One B-rep face of a CAD part: STEP entity #1128.
In plain terms, the planar face has unit normal (1, 0, 0).
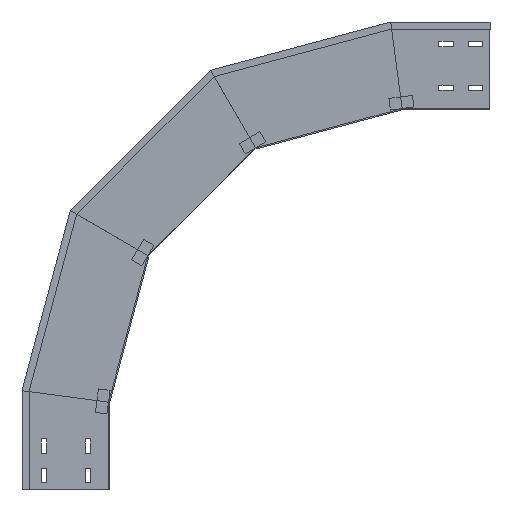
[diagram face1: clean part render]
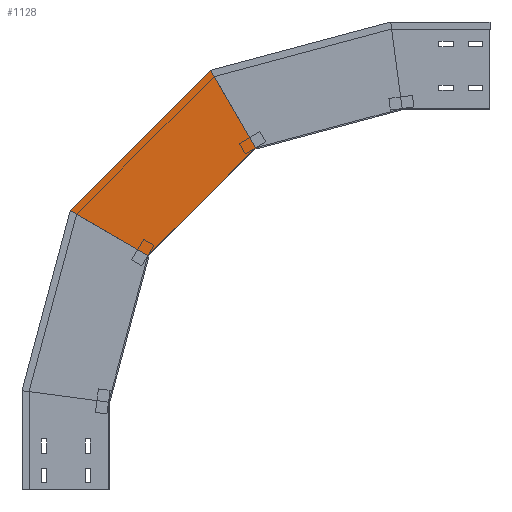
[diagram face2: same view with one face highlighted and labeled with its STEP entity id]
Its self-contained STEP definition (entity closure, numbers rounded to 3 decimals):
#20 = DIRECTION ( 'NONE',  ( 0., -0.5, -0.866 ) ) ;
#107 = CARTESIAN_POINT ( 'NONE',  ( 0., -250.175, 583.315 ) ) ;
#182 = EDGE_CURVE ( 'NONE', #1970, #1149, #2250, .T. ) ;
#220 = CARTESIAN_POINT ( 'NONE',  ( 0., -129.979, 363.834 ) ) ;
#388 = VECTOR ( 'NONE', #1787, 1000. ) ;
#463 = CARTESIAN_POINT ( 'NONE',  ( 0., -67.034, 400.175 ) ) ;
#530 = EDGE_CURVE ( 'NONE', #822, #1149, #2233, .T. ) ;
#629 = VERTEX_POINT ( 'NONE', #1124 ) ;
#787 = ORIENTED_EDGE ( 'NONE', *, *, #1533, .T. ) ;
#822 = VERTEX_POINT ( 'NONE', #1441 ) ;
#869 = EDGE_CURVE ( 'NONE', #629, #1970, #2286, .T. ) ;
#895 = DIRECTION ( 'NONE',  ( 1., 0., 0. ) ) ;
#1022 = CARTESIAN_POINT ( 'NONE',  ( 0., -35.701, 368.842 ) ) ;
#1105 = DIRECTION ( 'NONE',  ( 0., -0.707, 0.707 ) ) ;
#1124 = CARTESIAN_POINT ( 'NONE',  ( 0., 67.452, 477.821 ) ) ;
#1128 = ADVANCED_FACE ( 'NONE', ( #2009 ), #1277, .T. ) ;
#1149 = VERTEX_POINT ( 'NONE', #107 ) ;
#1277 = PLANE ( 'NONE',  #1401 ) ;
#1343 = DIRECTION ( 'NONE',  ( 0., -0.866, -0.5 ) ) ;
#1401 = AXIS2_PLACEMENT_3D ( 'NONE', #1022, #895, #2380 ) ;
#1406 = CARTESIAN_POINT ( 'NONE',  ( 0., 70.365, 474.908 ) ) ;
#1414 = VECTOR ( 'NONE', #20, 1000. ) ;
#1429 = ORIENTED_EDGE ( 'NONE', *, *, #182, .F. ) ;
#1441 = CARTESIAN_POINT ( 'NONE',  ( 0., -172.529, 717.802 ) ) ;
#1471 = ORIENTED_EDGE ( 'NONE', *, *, #869, .F. ) ;
#1533 = EDGE_CURVE ( 'NONE', #629, #822, #1620, .T. ) ;
#1620 = LINE ( 'NONE', #1406, #388 ) ;
#1787 = DIRECTION ( 'NONE',  ( 0., -0.707, 0.707 ) ) ;
#1858 = CARTESIAN_POINT ( 'NONE',  ( 0., -35.701, 368.842 ) ) ;
#1928 = EDGE_LOOP ( 'NONE', ( #787, #2375, #1429, #1471 ) ) ;
#1935 = VECTOR ( 'NONE', #1343, 1000. ) ;
#1970 = VERTEX_POINT ( 'NONE', #463 ) ;
#2009 = FACE_OUTER_BOUND ( 'NONE', #1928, .T. ) ;
#2233 = LINE ( 'NONE', #2267, #1414 ) ;
#2250 = LINE ( 'NONE', #1858, #2274 ) ;
#2267 = CARTESIAN_POINT ( 'NONE',  ( 0., -289.426, 515.33 ) ) ;
#2274 = VECTOR ( 'NONE', #1105, 1000. ) ;
#2286 = LINE ( 'NONE', #220, #1935 ) ;
#2375 = ORIENTED_EDGE ( 'NONE', *, *, #530, .T. ) ;
#2380 = DIRECTION ( 'NONE',  ( 0., 0., -1. ) ) ;
